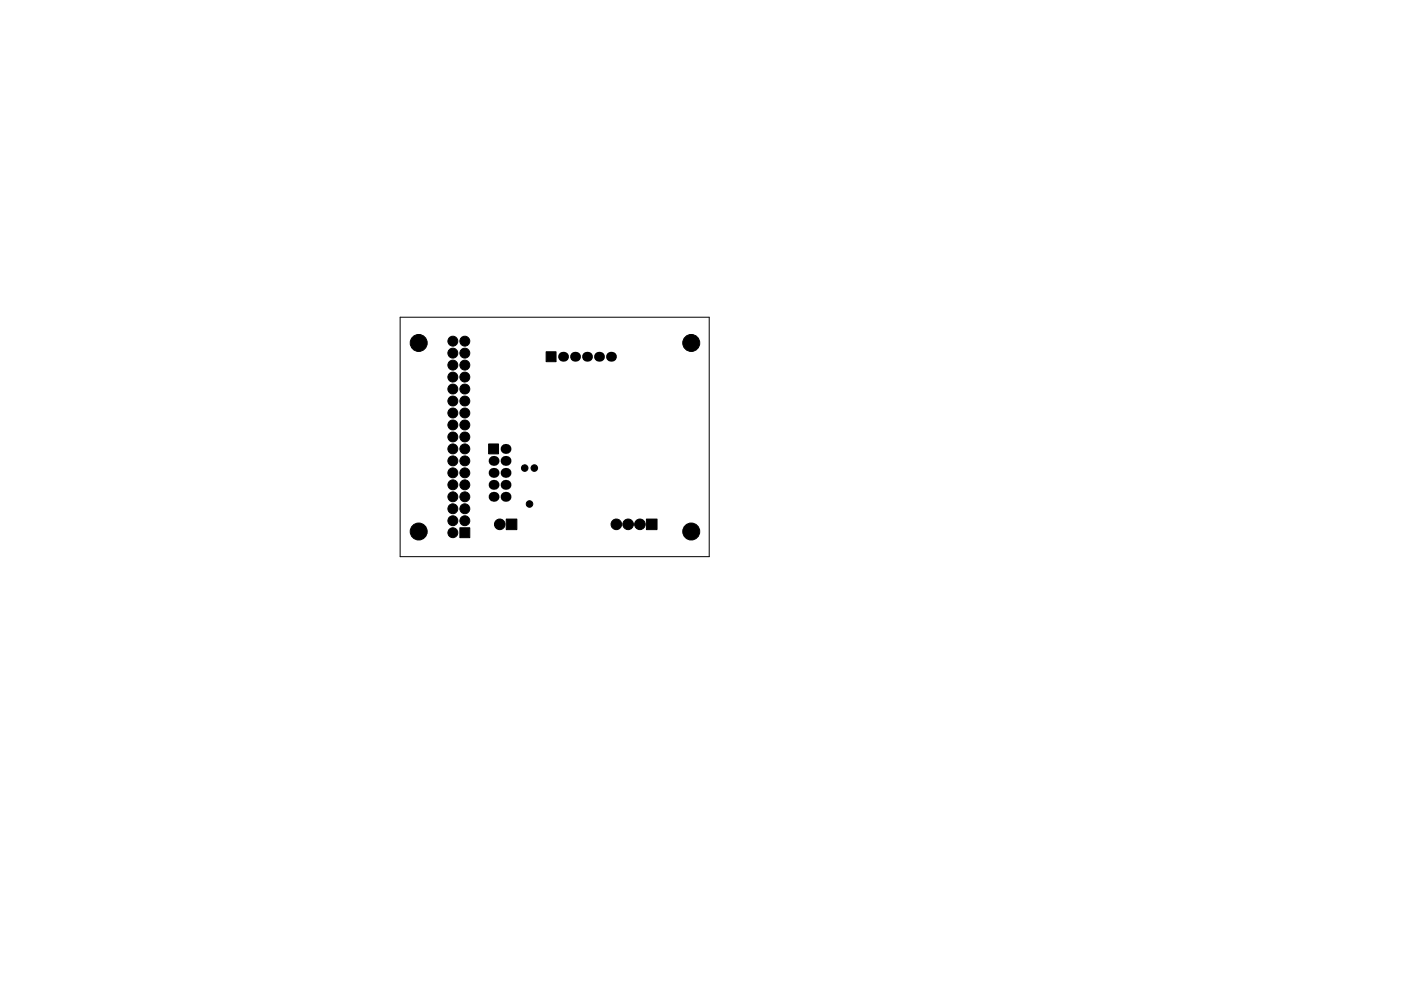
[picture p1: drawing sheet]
<svg xmlns="http://www.w3.org/2000/svg" width="297mm" height="210mm" viewBox="0 0 297 210" stroke-linecap="round" stroke-linejoin="round" font-family="sans-serif">
<path d="M84.8 67.3h65.6v50.8h-65.6z" fill="none" stroke="#000" stroke-width=".21"/>
<g fill="#000" stroke="#000" stroke-width=".21">
<path d="M115.8 74.6h2.1v2.1h-2.1zM103.6 94.2h2.1v2.1h-2.1zM97.5 112h2.1v2.1h-2.1zM107.3 110.1h2.3v2.3h-2.3zM137.1 110.1h2.2v2.3h-2.2z"/>
<circle cx="88.8" cy="72.8" r="1.8"/>
<circle cx="96" cy="72.4" r="1.05"/>
<circle cx="96" cy="77.5" r="1.05"/>
<circle cx="96" cy="74.9" r="1.05"/>
<circle cx="98.6" cy="77.5" r="1.05"/>
<circle cx="98.6" cy="74.9" r="1.05"/>
<circle cx="98.6" cy="72.4" r="1.05"/>
<circle cx="146.6" cy="72.8" r="1.8"/>
<circle cx="96" cy="95.2" r="1.05"/>
<circle cx="96" cy="92.7" r="1.05"/>
<circle cx="96" cy="82.5" r="1.05"/>
<circle cx="96" cy="87.6" r="1.05"/>
<circle cx="96" cy="90.2" r="1.05"/>
<circle cx="96" cy="85.1" r="1.05"/>
<circle cx="96" cy="97.8" r="1.05"/>
<circle cx="96" cy="80" r="1.05"/>
<circle cx="98.6" cy="82.5" r="1.05"/>
<circle cx="98.6" cy="95.2" r="1.05"/>
<circle cx="98.6" cy="92.7" r="1.05"/>
<circle cx="98.6" cy="80" r="1.05"/>
<circle cx="98.6" cy="87.6" r="1.05"/>
<circle cx="98.6" cy="97.8" r="1.05"/>
<circle cx="98.6" cy="85.1" r="1.05"/>
<circle cx="98.6" cy="90.2" r="1.05"/>
<circle cx="111.3" cy="99.3" r=".7"/>
<circle cx="113.3" cy="99.3" r=".7"/>
<circle cx="88.8" cy="112.8" r="1.8"/>
<circle cx="96" cy="105.4" r="1.05"/>
<circle cx="96" cy="110.5" r="1.05"/>
<circle cx="96" cy="100.3" r="1.05"/>
<circle cx="96" cy="107.9" r="1.05"/>
<circle cx="96" cy="102.9" r="1.05"/>
<circle cx="96" cy="113" r="1.05"/>
<circle cx="98.6" cy="110.5" r="1.05"/>
<circle cx="98.6" cy="102.9" r="1.05"/>
<circle cx="98.6" cy="105.4" r="1.05"/>
<circle cx="98.6" cy="107.9" r="1.05"/>
<circle cx="98.6" cy="100.3" r="1.05"/>
<circle cx="106" cy="111.2" r="1.12"/>
<circle cx="112.3" cy="106.9" r=".7"/>
<circle cx="130.7" cy="111.2" r="1.12"/>
<circle cx="133.2" cy="111.2" r="1.12"/>
<circle cx="135.7" cy="111.2" r="1.12"/>
<circle cx="146.6" cy="112.8" r="1.8"/>
</g>
<g fill="#000">
<circle cx="119.4" cy="75.7" r="1.05"/>
<circle cx="121.9" cy="75.7" r="1.05"/>
<circle cx="124.5" cy="75.7" r="1.05"/>
<circle cx="127" cy="75.7" r="1.05"/>
<circle cx="129.5" cy="75.7" r="1.05"/>
<circle cx="104.6" cy="97.8" r="1.05"/>
<circle cx="107.2" cy="97.8" r="1.05"/>
<circle cx="107.2" cy="95.2" r="1.05"/>
<circle cx="104.6" cy="105.4" r="1.05"/>
<circle cx="104.6" cy="100.3" r="1.05"/>
<circle cx="104.6" cy="102.9" r="1.05"/>
<circle cx="107.2" cy="105.4" r="1.05"/>
<circle cx="107.2" cy="102.9" r="1.05"/>
<circle cx="107.2" cy="100.3" r="1.05"/>
</g>
</svg>
